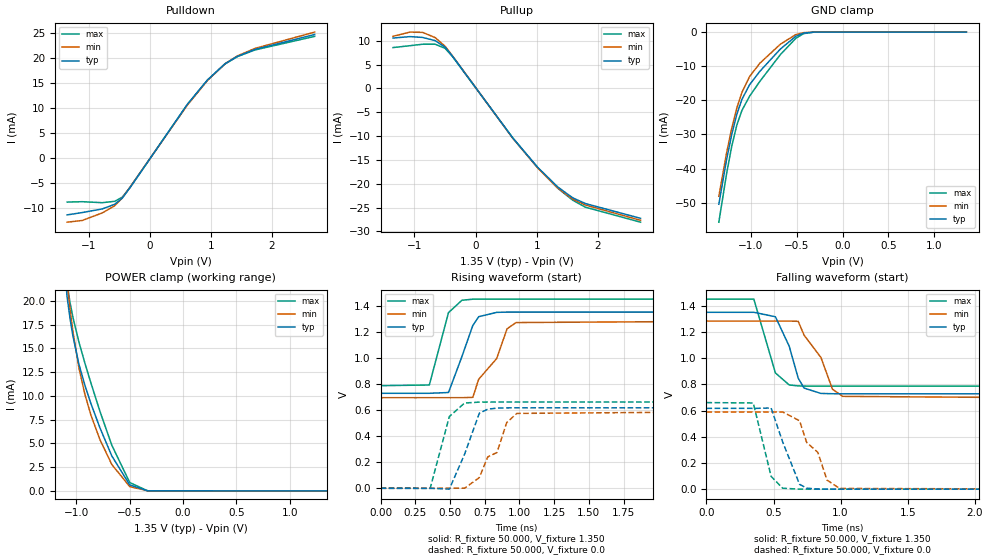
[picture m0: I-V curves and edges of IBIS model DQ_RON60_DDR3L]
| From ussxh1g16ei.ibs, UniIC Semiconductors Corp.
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|   Model DQ_RON60_DDR3L
[Model] DQ_RON60_DDR3L
Model_type I/O
Vinl =  0.540V
Vinh =  0.810V
Vmeas =  0.675V
Rref =  50.000
Vref =  0.675V
C_comp   1.224pF   1.223pF   1.239pF
[Model Spec]
Vinh   0.810V   0.776V   0.860V
Vinl   0.540V   0.506V   0.590V
Vmeas   0.675V   0.641V   0.725V
Vref   0.675V   0.641V   0.725V
Rref   50.000   NA   NA
[Temperature Range]   25.000   95.000   -40.000
[Voltage Range]   1.350V   1.283V   1.450V
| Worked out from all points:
|   slope of the pulldown table from 0 to 0.203 V, typ, clamps not added: 55.3 ohm
|   slope of the pullup table from 0 to 0.203 V, typ, clamps not added: 56.9 ohm
|   GND clamp passes 1 mA (typ) near -0.49 V on its own axis
|   POWER clamp passes 1 mA (typ) near -0.53 V on its own axis
|   rising waveform, R_fixture 50.000, V_fixture 1.350: 20-80 % time 138ps typ, 184ps min, 103ps max; typ from 0.728 V to 1.35 V
|   rising waveform, R_fixture 50.000, V_fixture 0.0: 20-80 % time 132ps typ, 175ps min, 100ps max; typ from 0 V to 0.617 V
|   falling waveform, R_fixture 50.000, V_fixture 1.350: 20-80 % time 140ps typ, 184ps min, 107ps max; typ from 1.35 V to 0.728 V
|   falling waveform, R_fixture 50.000, V_fixture 0.0: 20-80 % time 129ps typ, 173ps min, 96.8ps max; typ from 0.617 V to 0 V
[Pulldown]
|Voltage   I(typ)   I(min)   I(max)
-1.35V    -11.32mA   -12.77mA   -8.765mA
-1.104V   -10.85mA   -12.43mA   -8.687mA
-776mV    -10.13mA   -10.93mA   -8.883mA
-571mV    -9.195mA   -9.485mA   -8.61mA
-448mV    -7.97mA    -7.94mA    -7.779mA
-325mV    -5.951mA   -5.848mA   -5.918mA
618mV     10.72mA    10.58mA    10.69mA
946mV     15.57mA    15.46mA    15.52mA
1.233V    18.79mA    18.79mA    18.74mA
1.438V    20.27mA    20.37mA    20.22mA
1.725V    21.65mA    21.85mA    21.54mA
2.7V      24.61mA    25.09mA    24.24mA
[Pullup]
|Voltage   I(typ)   I(min)   I(max)
-1.35V    10.58mA    10.95mA    8.584mA
-1.072V   10.88mA    11.83mA    8.976mA
-867mV    10.71mA    11.77mA    9.283mA
-662mV    10.05mA    10.69mA    9.288mA
-498mV    8.669mA    8.868mA    8.429mA
-375mV    6.743mA    6.808mA    6.676mA
609mV     -10.37mA   -10.43mA   -10.37mA
1.019V    -16.56mA   -16.69mA   -16.65mA
1.347V    -20.68mA   -20.89mA   -20.95mA
1.593V    -22.96mA   -23.23mA   -23.46mA
1.798V    -24.14mA   -24.45mA   -24.9mA
2.7V      -27.24mA   -27.65mA   -28.05mA
[GND_clamp]
|Voltage   I(typ)   I(min)   I(max)
-1.35V    -50.46mA   -48.12mA   -55.72mA
-1.266V   -37.47mA   -35.5mA    -41.58mA
-1.21V    -30.09mA   -28.26mA   -33.55mA
-1.154V   -24.12mA   -22.27mA   -27.26mA
-1.098V   -19.71mA   -17.66mA   -22.94mA
-1.014V   -15.4mA    -13mA      -18.77mA
-902mV    -11.48mA   -9.107mA   -14.42mA
-678mV    -4.952mA   -3.532mA   -6.573mA
-510mV    -1.223mA   -723.8uA   -1.822mA
-426mV    -288.1uA   -165.1uA   -454.1uA
-314mV    -15.07uA   -12.09uA   -18.31uA
1.35V     0A         0A         0A
[POWER_clamp]
|Voltage   I(typ)   I(min)   I(max)
-1.35V    60.76mA    63.05mA    63.06mA
-1.086V   20.55mA    21.97mA    21.88mA
-1.058V   18.21mA    19.18mA    19.87mA
-1.03V    16.29mA    16.77mA    18.26mA
-974mV    13.34mA    12.95mA    15.67mA
-918mV    11.11mA    10.16mA    13.45mA
-862mV    9.205mA    7.993mA    11.37mA
-778mV    6.661mA    5.422mA    8.404mA
-666mV    3.683mA    2.783mA    4.812mA
-498mV    635.5uA    452.4uA    882.5uA
-330mV    13.33uA    16.29uA    10.16uA
1.35V     0A         0A         0A
[Ramp]
| variable   typ   min   max
dV/dt_r   0.370/0.132n   0.354/0.175n   0.397/0.100n
dV/dt_f   0.373/0.140n   0.353/0.184n   0.398/0.107n
R_load = 50.000
[Rising Waveform]
R_fixture= 50.000
V_fixture= 1.350
V_fixture_min= 1.283
V_fixture_max= 1.450
|time   V(typ)   V(min)   V(max)
0s        727.9mV    694.2mV    786.3mV
351ps     727.9mV    694.2mV    791.5mV
489ps     734mV      694.2mV    1.346V
586ps     1.01V      694.4mV    1.441V
664ps     1.247V     696.8mV    1.449V
707ps     1.315V     836.1mV    1.45V
836ps     1.348V     993.5mV    1.45V
911ps     1.35V      1.222V     1.45V
976ps     1.35V      1.27V      1.45V
3ns       1.35V      1.283V     1.45V
[Rising Waveform]
R_fixture= 50.000
V_fixture= 0.0
V_fixture_min= 0.0
V_fixture_max= 0.0
|time   V(typ)   V(min)   V(max)
0s        129nV      580.1nV    52.27nV
357ps     6.955uV    5.53uV     -989.3uV
495ps     -6.806mV   256.6nV    549.8mV
605ps     261.4mV    687.7uV    653.4mV
711ps     574.8mV    81.59mV    660.3mV
772ps     606.3mV    240.5mV    660.8mV
839ps     614.2mV    274.7mV    660.9mV
908ps     616.1mV    502.8mV    660.9mV
981ps     616.5mV    573.7mV    660.9mV
3ns       616.6mV    589.4mV    660.9mV
[Falling Waveform]
R_fixture= 50.000
V_fixture= 1.350
V_fixture_min= 1.283
V_fixture_max= 1.450
|time   V(typ)   V(min)   V(max)
0s        1.35V      1.283V     1.45V
353ps     1.35V      1.283V     1.451V
514ps     1.316V     1.283V     887.2mV
617ps     1.091V     1.283V     795.4mV
684ps     846.9mV    1.281V     788.2mV
728ps     771.4mV    1.175V     787mV
853ps     730.8mV    1.006V     786.3mV
939ps     728.4mV    763.7mV    786.3mV
1.015ns   728mV      708.3mV    786.3mV
3ns       727.9mV    694.2mV    786.3mV
[Falling Waveform]
R_fixture= 50.000
V_fixture= 0.0
V_fixture_min= 0.0
V_fixture_max= 0.0
|time   V(typ)   V(min)   V(max)
0s        616.6mV    589.4mV    660.9mV
349ps     616.6mV    589.4mV    657.9mV
482ps     619.4mV    589.4mV    97.77mV
568ps     360.8mV    589.2mV    7.242mV
694ps     37.07mV    522.2mV    154.2uV
747ps     7.802mV    356.4mV    29.96uV
830ps     673.3uV    281.3mV    2.584uV
899ps     86uV       69.15mV    543.4nV
992ps     5.694uV    5.445mV    278.8nV
3ns       294.5nV    659.8nV    239.6nV
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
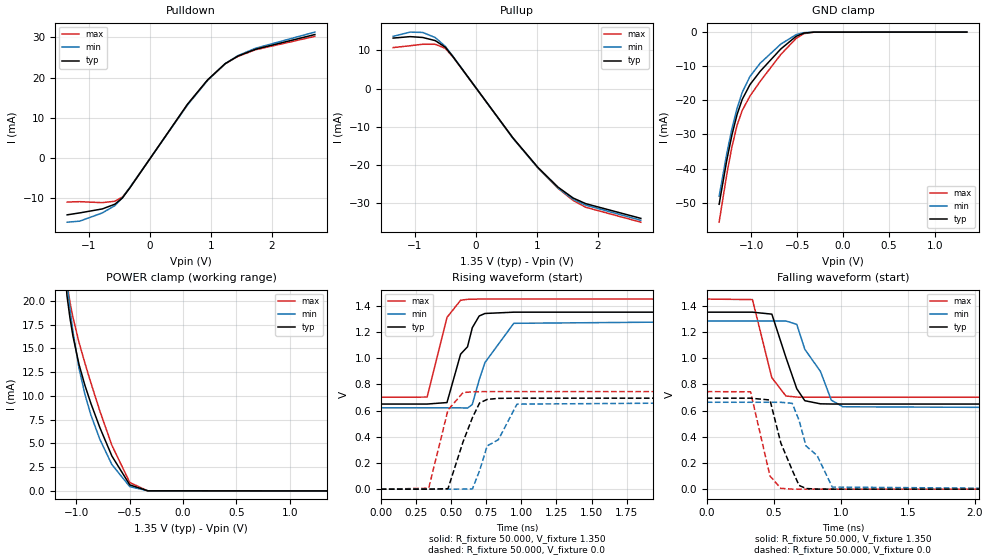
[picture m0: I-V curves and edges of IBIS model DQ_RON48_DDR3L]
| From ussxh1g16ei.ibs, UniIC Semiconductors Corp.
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|   Model DQ_RON48_DDR3L
[Model] DQ_RON48_DDR3L
Model_type I/O
Vinl =  0.540V
Vinh =  0.810V
Vmeas =  0.675V
Rref =  50.000
Vref =  0.675V
C_comp   1.224pF   1.223pF   1.239pF
[Model Spec]
Vinh   0.810V   0.776V   0.860V
Vinl   0.540V   0.506V   0.590V
Vmeas   0.675V   0.641V   0.725V
Vref   0.675V   0.641V   0.725V
Rref   50.000   NA   NA
[Temperature Range]   25.000   95.000   -40.000
[Voltage Range]   1.350V   1.283V   1.450V
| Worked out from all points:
|   slope of the pulldown table from 0 to 0.203 V, typ, clamps not added: 44.3 ohm
|   slope of the pullup table from 0 to 0.203 V, typ, clamps not added: 45.6 ohm
|   GND clamp passes 1 mA (typ) near -0.49 V on its own axis
|   POWER clamp passes 1 mA (typ) near -0.53 V on its own axis
|   rising waveform, R_fixture 50.000, V_fixture 1.350: 20-80 % time 140ps typ, 189ps min, 103ps max; typ from 0.649 V to 1.35 V
|   rising waveform, R_fixture 50.000, V_fixture 0.0: 20-80 % time 136ps typ, 182ps min, 102ps max; typ from 0 V to 0.694 V
|   falling waveform, R_fixture 50.000, V_fixture 1.350: 20-80 % time 141ps typ, 188ps min, 106ps max; typ from 1.35 V to 0.649 V
|   falling waveform, R_fixture 50.000, V_fixture 0.0: 20-80 % time 132ps typ, 178ps min, 96.3ps max; typ from 0.694 V to 0 V
[Pulldown]
|Voltage   I(typ)   I(min)   I(max)
-1.35V    -14.13mA   -15.96mA   -10.95mA
-1.145V   -13.65mA   -15.7mA    -10.85mA
-776mV    -12.66mA   -13.66mA   -11.1mA
-571mV    -11.49mA   -11.85mA   -10.76mA
-448mV    -9.956mA   -9.918mA   -9.718mA
-325mV    -7.433mA   -7.305mA   -7.392mA
618mV     13.39mA    13.21mA    13.35mA
946mV     19.45mA    19.31mA    19.38mA
1.233V    23.48mA    23.48mA    23.42mA
1.438V    25.33mA    25.45mA    25.26mA
1.725V    27.05mA    27.3mA     26.92mA
2.7V      30.73mA    31.34mA    30.27mA
[Pullup]
|Voltage   I(typ)   I(min)   I(max)
-1.35V    13.22mA    13.67mA    10.73mA
-1.072V   13.6mA     14.79mA    11.22mA
-867mV    13.38mA    14.7mA     11.6mA
-662mV    12.56mA    13.36mA    11.6mA
-498mV    10.83mA    11.07mA    10.53mA
-375mV    8.421mA    8.501mA    8.337mA
609mV     -12.94mA   -13.03mA   -12.95mA
1.019V    -20.68mA   -20.84mA   -20.79mA
1.347V    -25.83mA   -26.09mA   -26.16mA
1.593V    -28.67mA   -29mA      -29.3mA
1.798V    -30.14mA   -30.53mA   -31.09mA
2.7V      -34mA      -34.5mA    -35mA
[GND_clamp]
|Voltage   I(typ)   I(min)   I(max)
-1.35V    -50.46mA   -48.12mA   -55.72mA
-1.266V   -37.47mA   -35.5mA    -41.58mA
-1.21V    -30.09mA   -28.26mA   -33.55mA
-1.154V   -24.12mA   -22.27mA   -27.26mA
-1.098V   -19.71mA   -17.66mA   -22.94mA
-1.014V   -15.4mA    -13mA      -18.77mA
-902mV    -11.48mA   -9.107mA   -14.42mA
-678mV    -4.952mA   -3.532mA   -6.573mA
-510mV    -1.223mA   -723.8uA   -1.822mA
-426mV    -288.1uA   -165.1uA   -454.1uA
-314mV    -15.07uA   -12.09uA   -18.31uA
1.35V     0A         0A         0A
[POWER_clamp]
|Voltage   I(typ)   I(min)   I(max)
-1.35V    60.76mA    63.05mA    63.06mA
-1.086V   20.55mA    21.97mA    21.88mA
-1.058V   18.21mA    19.18mA    19.87mA
-1.03V    16.29mA    16.77mA    18.26mA
-974mV    13.34mA    12.95mA    15.67mA
-918mV    11.11mA    10.16mA    13.45mA
-862mV    9.205mA    7.993mA    11.37mA
-778mV    6.661mA    5.422mA    8.404mA
-666mV    3.683mA    2.783mA    4.812mA
-498mV    635.5uA    452.4uA    882.5uA
-330mV    13.33uA    16.29uA    10.16uA
1.35V     0A         0A         0A
[Ramp]
| variable   typ   min   max
dV/dt_r   0.416/0.135n   0.398/0.182n   0.446/0.102n
dV/dt_f   0.420/0.141n   0.398/0.188n   0.449/0.106n
R_load = 50.000
[Rising Waveform]
R_fixture= 50.000
V_fixture= 1.350
V_fixture_min= 1.283
V_fixture_max= 1.450
|time   V(typ)   V(min)   V(max)
0s        649.3mV    620.2mV    701.1mV
330ps     649.3mV    620.2mV    702.3mV
471ps     660.6mV    620.2mV    1.31V
568ps     1.03V      620.4mV    1.441V
617ps     1.086V     618.4mV    1.448V
651ps     1.231V     645.9mV    1.449V
700ps     1.321V     834mV      1.45V
741ps     1.34V      965.7mV    1.45V
946ps     1.35V      1.265V     1.45V
3ns       1.35V      1.283V     1.45V
[Rising Waveform]
R_fixture= 50.000
V_fixture= 0.0
V_fixture_min= 0.0
V_fixture_max= 0.0
|time   V(typ)   V(min)   V(max)
0s        115.5nV    519nV      47.02nV
341ps     13.19uV    7.575uV    7.063mV
478ps     3.474mV    2.062uV    603.8mV
585ps     360mV      608.4uV    736.5mV
652ps     545.7mV    2.233mV    742.8mV
703ps     657.5mV    141.6mV    743.8mV
757ps     684.6mV    329.9mV    744mV
837ps     692.6mV    377.7mV    744.1mV
969ps     694mV      648.8mV    744.1mV
3ns       694mV      662.8mV    744.1mV
[Falling Waveform]
R_fixture= 50.000
V_fixture= 1.350
V_fixture_min= 1.283
V_fixture_max= 1.450
|time   V(typ)   V(min)   V(max)
0s        1.35V      1.283V     1.45V
341ps     1.35V      1.283V     1.446V
486ps     1.335V     1.283V     850.2mV
591ps     1.005V     1.283V     710.7mV
672ps     766.1mV    1.257V     702.3mV
732ps     674.7mV    1.067V     701.4mV
849ps     650.9mV    897.8mV    701.2mV
930ps     649.5mV    678.9mV    701.1mV
1.017ns   649.3mV    628.3mV    701.1mV
3ns       649.3mV    620.2mV    701.1mV
[Falling Waveform]
R_fixture= 50.000
V_fixture= 0.0
V_fixture_min= 0.0
V_fixture_max= 0.0
|time   V(typ)   V(min)   V(max)
0s        694mV      662.8mV    744.1mV
327ps     694mV      662.7mV    742.7mV
472ps     680.1mV    662.8mV    100.4mV
553ps     352mV      662.5mV    6.416mV
638ps     145.5mV    654.9mV    338.9uV
689ps     28.83mV    525.3mV    57.22uV
741ps     5.176mV    329.8mV    9.49uV
824ps     344.7uV    256.3mV    716.5nV
937ps     8.14uV     15.96mV    207.4nV
3ns       236nV      614nV      162.3nV
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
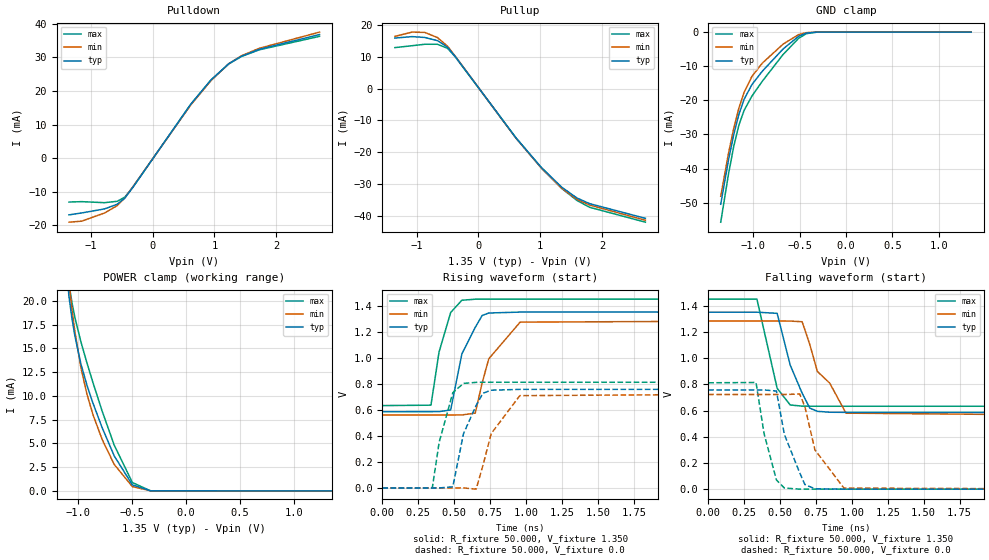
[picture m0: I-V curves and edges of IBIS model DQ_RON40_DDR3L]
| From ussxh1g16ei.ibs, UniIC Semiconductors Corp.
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|   Model DQ_RON40_DDR3L
[Model] DQ_RON40_DDR3L
Model_type I/O
Vinl =  0.540V
Vinh =  0.810V
Vmeas =  0.675V
Rref =  50.000
Vref =  0.675V
C_comp   1.224pF   1.223pF   1.239pF
[Model Spec]
Vinh   0.810V   0.776V   0.860V
Vinl   0.540V   0.506V   0.590V
Vmeas   0.675V   0.641V   0.725V
Vref   0.675V   0.641V   0.725V
Rref   50.000   NA   NA
[Temperature Range]   25.000   95.000   -40.000
[Voltage Range]   1.350V   1.283V   1.450V
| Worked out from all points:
|   slope of the pulldown table from 0 to 0.203 V, typ, clamps not added: 36.9 ohm
|   slope of the pullup table from 0 to 0.203 V, typ, clamps not added: 38 ohm
|   GND clamp passes 1 mA (typ) near -0.49 V on its own axis
|   POWER clamp passes 1 mA (typ) near -0.53 V on its own axis
|   rising waveform, R_fixture 50.000, V_fixture 1.350: 20-80 % time 135ps typ, 186ps min, 97.9ps max; typ from 0.586 V to 1.35 V
|   rising waveform, R_fixture 50.000, V_fixture 0.0: 20-80 % time 130ps typ, 179ps min, 96.1ps max; typ from 0 V to 0.757 V
|   falling waveform, R_fixture 50.000, V_fixture 1.350: 20-80 % time 136ps typ, 183ps min, 99.6ps max; typ from 1.35 V to 0.586 V
|   falling waveform, R_fixture 50.000, V_fixture 0.0: 20-80 % time 127ps typ, 173ps min, 90.8ps max; typ from 0.757 V to 0 V
[Pulldown]
|Voltage   I(typ)   I(min)   I(max)
-1.35V    -16.95mA   -19.14mA   -13.13mA
-1.145V   -16.38mA   -18.83mA   -13.01mA
-776mV    -15.18mA   -16.39mA   -13.32mA
-571mV    -13.78mA   -14.21mA   -12.91mA
-448mV    -11.94mA   -11.89mA   -11.65mA
-325mV    -8.911mA   -8.758mA   -8.862mA
618mV     16.06mA    15.84mA    16.01mA
946mV     23.33mA    23.15mA    23.24mA
1.233V    28.15mA    28.15mA    28.08mA
1.438V    30.37mA    30.51mA    30.3mA
1.725V    32.43mA    32.73mA    32.28mA
2.7V      36.84mA    37.57mA    36.3mA
[Pullup]
|Voltage   I(typ)   I(min)   I(max)
-1.35V    15.86mA    16.4mA     12.87mA
-1.072V   16.32mA    17.74mA    13.46mA
-867mV    16.05mA    17.64mA    13.92mA
-662mV    15.06mA    16.02mA    13.92mA
-498mV    12.98mA    13.28mA    12.63mA
-375mV    10.1mA     10.19mA    9.994mA
609mV     -15.52mA   -15.62mA   -15.52mA
1.019V    -24.79mA   -24.98mA   -24.92mA
1.347V    -30.96mA   -31.27mA   -31.36mA
1.593V    -34.36mA   -34.76mA   -35.13mA
1.798V    -36.13mA   -36.58mA   -37.28mA
2.7V      -40.75mA   -41.34mA   -41.96mA
[GND_clamp]
|Voltage   I(typ)   I(min)   I(max)
-1.35V    -50.46mA   -48.12mA   -55.72mA
-1.266V   -37.47mA   -35.5mA    -41.58mA
-1.21V    -30.09mA   -28.26mA   -33.55mA
-1.154V   -24.12mA   -22.27mA   -27.26mA
-1.098V   -19.71mA   -17.66mA   -22.94mA
-1.014V   -15.4mA    -13mA      -18.77mA
-902mV    -11.48mA   -9.107mA   -14.42mA
-678mV    -4.952mA   -3.532mA   -6.573mA
-510mV    -1.223mA   -723.8uA   -1.822mA
-426mV    -288.1uA   -165.1uA   -454.1uA
-314mV    -15.07uA   -12.09uA   -18.31uA
1.35V     0A         0A         0A
[POWER_clamp]
|Voltage   I(typ)   I(min)   I(max)
-1.35V    60.76mA    63.05mA    63.06mA
-1.086V   20.55mA    21.97mA    21.88mA
-1.058V   18.21mA    19.18mA    19.87mA
-1.03V    16.29mA    16.77mA    18.26mA
-974mV    13.34mA    12.95mA    15.67mA
-918mV    11.11mA    10.16mA    13.45mA
-862mV    9.205mA    7.993mA    11.37mA
-778mV    6.661mA    5.422mA    8.404mA
-666mV    3.683mA    2.783mA    4.812mA
-498mV    635.5uA    452.4uA    882.5uA
-330mV    13.33uA    16.29uA    10.16uA
1.35V     0A         0A         0A
[Ramp]
| variable   typ   min   max
dV/dt_r   0.454/0.131n   0.433/0.178n   0.487/96.070p
dV/dt_f   0.458/0.136n   0.434/0.183n   0.491/99.504p
R_load = 50.000
[Rising Waveform]
R_fixture= 50.000
V_fixture= 1.350
V_fixture_min= 1.283
V_fixture_max= 1.450
|time   V(typ)   V(min)   V(max)
0s        585.8mV    560.4mV    632.4mV
338ps     585.9mV    560.4mV    635.5mV
394ps     586mV      560.4mV    1.043V
475ps     598.6mV    560.4mV    1.347V
553ps     1.029V     560.6mV    1.441V
646ps     1.233V     574.8mV    1.449V
694ps     1.324V     806.7mV    1.45V
740ps     1.343V     991.4mV    1.45V
958ps     1.35V      1.273V     1.45V
3ns       1.35V      1.283V     1.45V
[Rising Waveform]
R_fixture= 50.000
V_fixture= 0.0
V_fixture_min= 0.0
V_fixture_max= 0.0
|time   V(typ)   V(min)   V(max)
0s        104.7nV    469.8nV    42.78nV
347ps     4.56uV     8.353uV    -637.1uV
395ps     85.74uV    13.47uV    351.2mV
490ps     9.118mV    -14.13uV   731.6mV
564ps     416.3mV    558.8uV    802.7mV
652ps     633.3mV    -9.162mV   810.8mV
699ps     726.9mV    172.2mV    811.4mV
757ps     750.5mV    418.1mV    811.5mV
956ps     756.8mV    708.7mV    811.5mV
3ns       756.8mV    722.2mV    811.5mV
[Falling Waveform]
R_fixture= 50.000
V_fixture= 1.350
V_fixture_min= 1.283
V_fixture_max= 1.450
|time   V(typ)   V(min)   V(max)
0s        1.35V      1.283V     1.45V
339ps     1.35V      1.283V     1.45V
480ps     1.341V     1.283V     769.2mV
571ps     946mV      1.282V     642.2mV
654ps     732mV      1.277V     633.3mV
707ps     618.5mV    1.104V     632.6mV
760ps     593.8mV    898.1mV    632.5mV
846ps     586.8mV    808.8mV    632.4mV
959ps     585.9mV    579.9mV    632.4mV
3ns       585.8mV    560.4mV    632.4mV
[Falling Waveform]
R_fixture= 50.000
V_fixture= 0.0
V_fixture_min= 0.0
V_fixture_max= 0.0
|time   V(typ)   V(min)   V(max)
0s        756.8mV    722.2mV    811.5mV
333ps     756.8mV    722.2mV    813.6mV
389ps     756.6mV    722.2mV    423.2mV
475ps     748.4mV    722.2mV    70.11mV
530ps     418.3mV    722mV      8.663mV
637ps     124.6mV    725.8mV    145.5uV
673ps     35.09mV    629.6mV    36.05uV
743ps     2.77mV     299.3mV    2.528uV
945ps     1.878uV    8.14mV     168.1nV
3ns       188.4nV    546.5nV    123.2nV
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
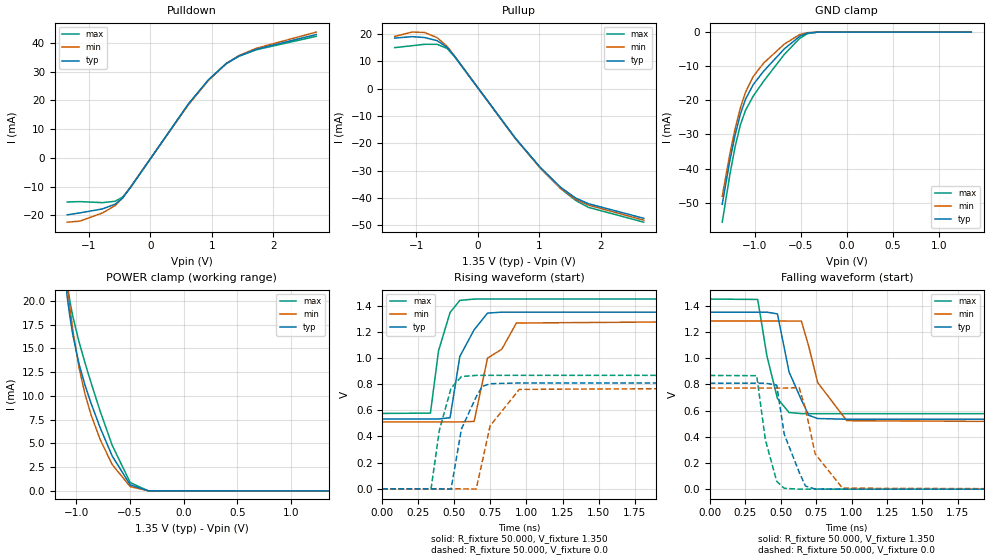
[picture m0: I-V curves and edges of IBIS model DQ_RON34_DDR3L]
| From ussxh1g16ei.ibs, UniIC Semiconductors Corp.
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|   Model DQ_RON34_DDR3L
[Model] DQ_RON34_DDR3L
Model_type I/O
Vinl =  0.540V
Vinh =  0.810V
Vmeas =  0.675V
Rref =  50.000
Vref =  0.675V
C_comp   1.224pF   1.223pF   1.239pF
[Model Spec]
Vinh   0.810V   0.776V   0.860V
Vinl   0.540V   0.506V   0.590V
Vmeas   0.675V   0.641V   0.725V
Vref   0.675V   0.641V   0.725V
Rref   50.000   NA   NA
[Temperature Range]   25.000   95.000   -40.000
[Voltage Range]   1.350V   1.283V   1.450V
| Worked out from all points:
|   slope of the pulldown table from 0 to 0.203 V, typ, clamps not added: 31.7 ohm
|   slope of the pullup table from 0 to 0.203 V, typ, clamps not added: 32.6 ohm
|   GND clamp passes 1 mA (typ) near -0.49 V on its own axis
|   POWER clamp passes 1 mA (typ) near -0.53 V on its own axis
|   rising waveform, R_fixture 50.000, V_fixture 1.350: 20-80 % time 134ps typ, 186ps min, 96.2ps max; typ from 0.534 V to 1.35 V
|   rising waveform, R_fixture 50.000, V_fixture 0.0: 20-80 % time 130ps typ, 179ps min, 94.9ps max; typ from 0 V to 0.809 V
|   falling waveform, R_fixture 50.000, V_fixture 1.350: 20-80 % time 133ps typ, 180ps min, 95.6ps max; typ from 1.35 V to 0.534 V
|   falling waveform, R_fixture 50.000, V_fixture 0.0: 20-80 % time 125ps typ, 171ps min, 88.4ps max; typ from 0.809 V to 0 V
[Pulldown]
|Voltage   I(typ)   I(min)   I(max)
-1.35V    -19.77mA   -22.33mA   -15.31mA
-1.145V   -19.1mA    -21.96mA   -15.17mA
-776mV    -17.71mA   -19.11mA   -15.53mA
-571mV    -16.07mA   -16.57mA   -15.05mA
-448mV    -13.92mA   -13.86mA   -13.59mA
-325mV    -10.39mA   -10.21mA   -10.33mA
618mV     18.72mA    18.46mA    18.66mA
946mV     27.19mA    26.98mA    27.09mA
1.233V    32.82mA    32.81mA    32.73mA
1.438V    35.41mA    35.57mA    35.32mA
1.725V    37.81mA    38.16mA    37.64mA
2.7V      42.94mA    43.78mA    42.31mA
[Pullup]
|Voltage   I(typ)   I(min)   I(max)
-1.35V    18.5mA     19.12mA    15.01mA
-1.072V   19.03mA    20.7mA     15.7mA
-867mV    18.71mA    20.57mA    16.23mA
-662mV    17.56mA    18.68mA    16.23mA
-498mV    15.13mA    15.48mA    14.72mA
-375mV    11.76mA    11.88mA    11.65mA
609mV     -18.08mA   -18.2mA    -18.08mA
1.019V    -28.88mA   -29.11mA   -29.04mA
1.347V    -36.08mA   -36.43mA   -36.54mA
1.593V    -40.04mA   -40.5mA    -40.93mA
1.798V    -42.1mA    -42.62mA   -43.44mA
2.7V      -47.46mA   -48.14mA   -48.88mA
[GND_clamp]
|Voltage   I(typ)   I(min)   I(max)
-1.35V    -50.46mA   -48.12mA   -55.72mA
-1.266V   -37.47mA   -35.5mA    -41.58mA
-1.21V    -30.09mA   -28.26mA   -33.55mA
-1.154V   -24.12mA   -22.27mA   -27.26mA
-1.098V   -19.71mA   -17.66mA   -22.94mA
-1.014V   -15.4mA    -13mA      -18.77mA
-902mV    -11.48mA   -9.107mA   -14.42mA
-678mV    -4.952mA   -3.532mA   -6.573mA
-510mV    -1.223mA   -723.8uA   -1.822mA
-426mV    -288.1uA   -165.1uA   -454.1uA
-314mV    -15.07uA   -12.09uA   -18.31uA
1.35V     0A         0A         0A
[POWER_clamp]
|Voltage   I(typ)   I(min)   I(max)
-1.35V    60.76mA    63.05mA    63.06mA
-1.086V   20.55mA    21.97mA    21.88mA
-1.058V   18.21mA    19.18mA    19.87mA
-1.03V    16.29mA    16.77mA    18.26mA
-974mV    13.34mA    12.95mA    15.67mA
-918mV    11.11mA    10.16mA    13.45mA
-862mV    9.205mA    7.993mA    11.37mA
-778mV    6.661mA    5.422mA    8.404mA
-666mV    3.683mA    2.783mA    4.812mA
-498mV    635.5uA    452.4uA    882.5uA
-330mV    13.33uA    16.29uA    10.16uA
1.35V     0A         0A         0A
[Ramp]
| variable   typ   min   max
dV/dt_r   0.485/0.130n   0.463/0.179n   0.520/94.856p
dV/dt_f   0.490/0.132n   0.463/0.180n   0.524/95.446p
R_load = 50.000
[Rising Waveform]
R_fixture= 50.000
V_fixture= 1.350
V_fixture_min= 1.283
V_fixture_max= 1.450
|time   V(typ)   V(min)   V(max)
0s        533.7mV    511.1mV    576mV
334ps     533.7mV    511.1mV    578.6mV
390ps     533.9mV    511.1mV    1.054V
470ps     543.2mV    511.1mV    1.347V
538ps     1.012V     511.3mV    1.44V
637ps     1.215V     515mV      1.45V
730ps     1.343V     998.9mV    1.45V
829ps     1.35V      1.067V     1.45V
930ps     1.35V      1.267V     1.45V
3ns       1.35V      1.283V     1.45V
[Rising Waveform]
R_fixture= 50.000
V_fixture= 0.0
V_fixture_min= 0.0
V_fixture_max= 0.0
|time   V(typ)   V(min)   V(max)
0s        95.71nV    429.1nV    39.3nV
338ps     22.37uV    10.14uV    -2.215mV
396ps     240.6uV    15.83uV    448.5mV
477ps     -2.659mV   -5.63uV    768.8mV
549ps     457mV      446.4uV    857.9mV
651ps     702mV      -2.325mV   866.8mV
693ps     782mV      205.9mV    867.1mV
748ps     803.2mV    482.3mV    867.1mV
950ps     808.6mV    759.7mV    867.2mV
3ns       808.6mV    771.2mV    867.2mV
[Falling Waveform]
R_fixture= 50.000
V_fixture= 1.350
V_fixture_min= 1.283
V_fixture_max= 1.450
|time   V(typ)   V(min)   V(max)
0s        1.35V      1.283V     1.45V
338ps     1.35V      1.283V     1.447V
403ps     1.35V      1.283V     1.016V
477ps     1.337V     1.283V     692.1mV
559ps     893.9mV    1.282V     584.6mV
646ps     681.2mV    1.282V     576.5mV
698ps     563.3mV    1.089V     576.1mV
761ps     538.6mV    812.8mV    576mV
966ps     533.7mV    522.4mV    576mV
3ns       533.7mV    511.1mV    576mV
[Falling Waveform]
R_fixture= 50.000
V_fixture= 0.0
V_fixture_min= 0.0
V_fixture_max= 0.0
|time   V(typ)   V(min)   V(max)
0s        808.6mV    771.2mV    867.2mV
331ps     808.5mV    771.2mV    865.7mV
392ps     808.2mV    771.2mV    376.3mV
472ps     793.5mV    771.1mV    59.71mV
525ps     418.8mV    770.9mV    6.614mV
630ps     130.8mV    775.1mV    75.03uV
675ps     23.63mV    613.4mV    11.17uV
743ps     1.587mV    269.6mV    762.7nV
936ps     852.3nV    7.514mV    130nV
3ns       -34.23nV   495.5nV    75.89nV
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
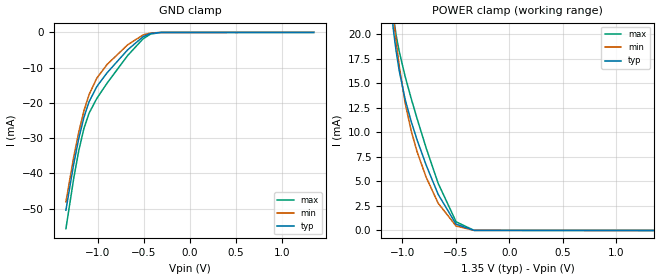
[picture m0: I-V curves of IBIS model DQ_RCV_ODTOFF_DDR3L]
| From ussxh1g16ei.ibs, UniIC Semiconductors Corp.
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|   Model DQ_RCV_ODTOFF_DDR3L
[Model] DQ_RCV_ODTOFF_DDR3L
Model_type Input
Vinl =  0.540V
Vinh =  0.810V
C_comp   1.224pF   1.223pF   1.239pF
[Model Spec]
Vinh   0.810V   0.776V   0.860V
Vinl   0.540V   0.506V   0.590V
[Temperature Range]   25.000   95.000   -40.000
[Voltage Range]   1.350V   1.283V   1.450V
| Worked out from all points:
|   GND clamp passes 1 mA (typ) near -0.49 V on its own axis
|   POWER clamp passes 1 mA (typ) near -0.53 V on its own axis
[GND_clamp]
|Voltage   I(typ)   I(min)   I(max)
-1.35V    -50.46mA   -48.12mA   -55.72mA
-1.266V   -37.47mA   -35.5mA    -41.58mA
-1.21V    -30.09mA   -28.26mA   -33.55mA
-1.154V   -24.12mA   -22.27mA   -27.26mA
-1.098V   -19.71mA   -17.66mA   -22.94mA
-1.014V   -15.4mA    -13mA      -18.77mA
-902mV    -11.48mA   -9.107mA   -14.42mA
-678mV    -4.952mA   -3.532mA   -6.573mA
-510mV    -1.223mA   -723.8uA   -1.822mA
-426mV    -288.1uA   -165.1uA   -454.1uA
-314mV    -15.07uA   -12.09uA   -18.31uA
1.35V     0A         0A         0A
[POWER_clamp]
|Voltage   I(typ)   I(min)   I(max)
-1.35V    60.76mA    63.05mA    63.06mA
-1.086V   20.55mA    21.97mA    21.88mA
-1.058V   18.21mA    19.18mA    19.87mA
-1.03V    16.29mA    16.77mA    18.26mA
-974mV    13.34mA    12.95mA    15.67mA
-918mV    11.11mA    10.16mA    13.45mA
-862mV    9.205mA    7.993mA    11.37mA
-778mV    6.661mA    5.422mA    8.404mA
-666mV    3.683mA    2.783mA    4.812mA
-498mV    635.5uA    452.4uA    882.5uA
-330mV    13.33uA    16.29uA    10.16uA
1.35V     0A         0A         0A
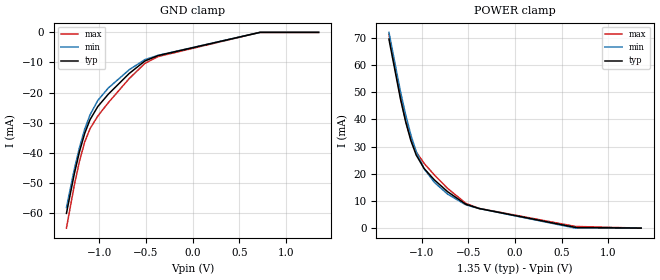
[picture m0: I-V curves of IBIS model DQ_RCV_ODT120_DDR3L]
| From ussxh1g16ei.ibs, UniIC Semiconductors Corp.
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|   Model DQ_RCV_ODT120_DDR3L
[Model] DQ_RCV_ODT120_DDR3L
Model_type Input
Vinl =  0.540V
Vinh =  0.810V
C_comp   1.224pF   1.223pF   1.239pF
[Model Spec]
Vinh   0.810V   0.776V   0.860V
Vinl   0.540V   0.506V   0.590V
[Temperature Range]   25.000   95.000   -40.000
[Voltage Range]   1.350V   1.283V   1.450V
[GND_clamp]
|Voltage   I(typ)   I(min)   I(max)
-1.35V    -60.1mA    -58.18mA   -65mA
-1.266V   -47.01mA   -45.48mA   -50.78mA
-1.21V    -39.55mA   -38.18mA   -42.7mA
-1.154V   -33.5mA    -32.11mA   -36.36mA
-1.098V   -29.02mA   -27.41mA   -32mA
-1.014V   -24.61mA   -22.6mA    -27.77mA
-902mV    -20.53mA   -18.48mA   -23.36mA
-678mV    -13.65mA   -12.41mA   -15.34mA
-510mV    -9.504mA   -9.046mA   -10.31mA
-370mV    -7.712mA   -7.635mA   -8.043mA
722mV     0A         0A         0A
1.35V     0A         0A         0A
[POWER_clamp]
|Voltage   I(typ)   I(min)   I(max)
-1.35V    69.54mA    72.01mA    71.31mA
-1.226V   47.43mA    50.15mA    48.1mA
-1.17V    38.99mA    41.55mA    39.37mA
-1.114V   32.05mA    34.13mA    32.59mA
-1.058V   26.89mA    28.15mA    28.06mA
-974mV    21.95mA    21.87mA    23.84mA
-862mV    17.69mA    16.78mA    19.5mA
-722mV    13.4mA     12.52mA    14.61mA
-526mV    8.771mA    8.554mA    9.101mA
-386mV    7.226mA    7.219mA    7.269mA
650mV     248.1uA    0A         611.8uA
1.35V     0A         0A         0A
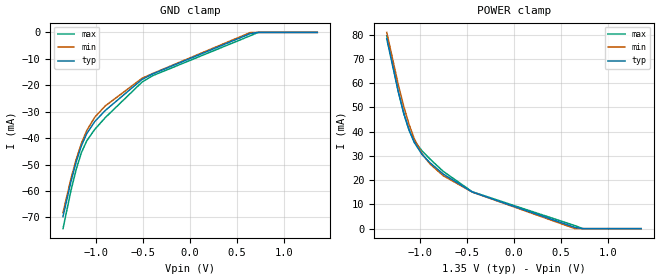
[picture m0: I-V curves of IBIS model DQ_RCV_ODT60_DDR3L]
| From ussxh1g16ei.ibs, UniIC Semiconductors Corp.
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|   Model DQ_RCV_ODT60_DDR3L
[Model] DQ_RCV_ODT60_DDR3L
Model_type Input
Vinl =  0.540V
Vinh =  0.810V
C_comp   1.224pF   1.223pF   1.239pF
[Model Spec]
Vinh   0.810V   0.776V   0.860V
Vinl   0.540V   0.506V   0.590V
[Temperature Range]   25.000   95.000   -40.000
[Voltage Range]   1.350V   1.283V   1.450V
[GND_clamp]
|Voltage   I(typ)   I(min)   I(max)
-1.35V    -69.73mA   -68.22mA   -74.28mA
-1.266V   -56.53mA   -55.44mA   -59.97mA
-1.21V    -49.01mA   -48.08mA   -51.85mA
-1.154V   -42.88mA   -41.94mA   -45.46mA
-1.098V   -38.33mA   -37.15mA   -41.06mA
-1.014V   -33.8mA    -32.18mA   -36.77mA
-902mV    -29.58mA   -27.84mA   -32.29mA
-510mV    -17.77mA   -17.35mA   -18.78mA
-398mV    -15.72mA   -15.57mA   -16.38mA
638mV     -478.2uA   -60.2uA    -1.282mA
722mV     0A         0A         0A
1.35V     0A         0A         0A
[POWER_clamp]
|Voltage   I(typ)   I(min)   I(max)
-1.35V    78.34mA    80.97mA    79.58mA
-1.226V   56.2mA     59.14mA    56.33mA
-1.17V    47.74mA    50.54mA    47.59mA
-1.114V   40.76mA    43.12mA    40.8mA
-1.058V   35.56mA    37.11mA    36.26mA
-974mV    30.56mA    30.78mA    32.02mA
-890mV    27.17mA    26.67mA    28.7mA
-750mV    22.54mA    21.84mA    23.63mA
-442mV    15.11mA    15.09mA    15.22mA
650mV     495.9uA    0A         1.223mA
734mV     0A         0A         0A
1.35V     0A         0A         0A
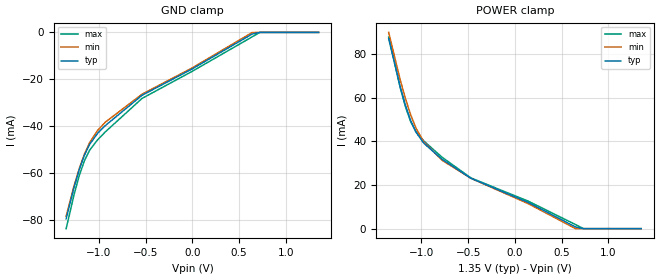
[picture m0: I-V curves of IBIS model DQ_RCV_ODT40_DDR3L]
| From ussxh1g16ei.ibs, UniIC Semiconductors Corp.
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|   Model DQ_RCV_ODT40_DDR3L
[Model] DQ_RCV_ODT40_DDR3L
Model_type Input
Vinl =  0.540V
Vinh =  0.810V
C_comp   1.224pF   1.223pF   1.239pF
[Model Spec]
Vinh   0.810V   0.776V   0.860V
Vinl   0.540V   0.506V   0.590V
[Temperature Range]   25.000   95.000   -40.000
[Voltage Range]   1.350V   1.283V   1.450V
[GND_clamp]
|Voltage   I(typ)   I(min)   I(max)
-1.35V    -79.32mA   -78.22mA   -83.51mA
-1.266V   -66.02mA   -65.37mA   -69.13mA
-1.21V    -58.42mA   -57.95mA   -60.95mA
-1.154V   -52.22mA   -51.73mA   -54.52mA
-1.098V   -47.59mA   -46.85mA   -50.07mA
-1.014V   -42.96mA   -41.72mA   -45.74mA
-930mV    -39.61mA   -38.17mA   -42.29mA
-538mV    -26.75mA   -26.28mA   -28.08mA
-6mV      -15.62mA   -15.2mA    -16.65mA
638mV     -714.4uA   -88.57uA   -1.918mA
722mV     0A         0A         0A
1.35V     0A         0A         0A
[POWER_clamp]
|Voltage   I(typ)   I(min)   I(max)
-1.35V    87.11mA    89.91mA    87.81mA
-1.226V   64.95mA    68.1mA     64.54mA
-1.17V    56.46mA    59.51mA    55.79mA
-1.114V   49.45mA    52.08mA    48.98mA
-1.058V   44.22mA    46.06mA    44.43mA
-974mV    39.14mA    39.68mA    40.17mA
-778mV    31.77mA    31.3mA     32.7mA
-470mV    23.08mA    23.06mA    23.24mA
146mV     11.94mA    11.39mA    12.54mA
650mV     743.3uA    0A         1.832mA
734mV     0A         0A         0A
1.35V     0A         0A         0A
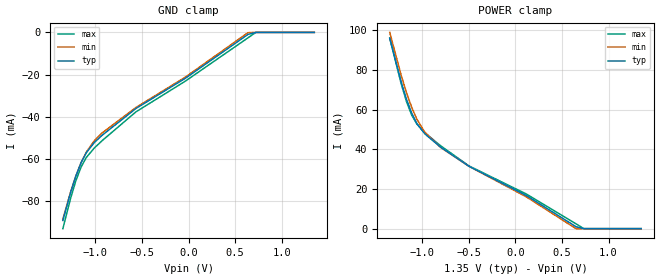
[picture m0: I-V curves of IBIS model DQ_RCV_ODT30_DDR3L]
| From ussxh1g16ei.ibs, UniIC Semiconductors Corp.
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|   Model DQ_RCV_ODT30_DDR3L
[Model] DQ_RCV_ODT30_DDR3L
Model_type Input
Vinl =  0.540V
Vinh =  0.810V
C_comp   1.224pF   1.223pF   1.239pF
[Model Spec]
Vinh   0.810V   0.776V   0.860V
Vinl   0.540V   0.506V   0.590V
[Temperature Range]   25.000   95.000   -40.000
[Voltage Range]   1.350V   1.283V   1.450V
[GND_clamp]
|Voltage   I(typ)   I(min)   I(max)
-1.35V    -89.01mA   -88.32mA   -92.86mA
-1.266V   -75.6mA    -75.39mA   -78.39mA
-1.21V    -67.93mA   -67.91mA   -70.16mA
-1.154V   -61.65mA   -61.61mA   -63.69mA
-1.098V   -56.95mA   -56.64mA   -59.19mA
-1.014V   -52.21mA   -51.35mA   -54.79mA
-930mV    -48.74mA   -47.63mA   -51.29mA
-566mV    -36.03mA   -35.54mA   -37.62mA
-34mV     -21.68mA   -21.14mA   -23.04mA
638mV     -958.1uA   -121.4uA   -2.565mA
722mV     0A         0A         0A
1.35V     0A         0A         0A
[POWER_clamp]
|Voltage   I(typ)   I(min)   I(max)
-1.35V    95.95mA    98.92mA    96.13mA
-1.226V   73.77mA    77.14mA    72.83mA
-1.17V    65.26mA    68.55mA    64.06mA
-1.114V   58.22mA    61.12mA    57.24mA
-1.058V   52.94mA    55.09mA    52.67mA
-974mV    47.8mA     48.65mA    48.39mA
-806mV    41.17mA    41mA       41.87mA
-498mV    31.41mA    31.4mA     31.6mA
118mV     16.68mA    16mA       17.44mA
650mV     989uA      0A         2.443mA
734mV     0A         0A         0A
1.35V     0A         0A         0A
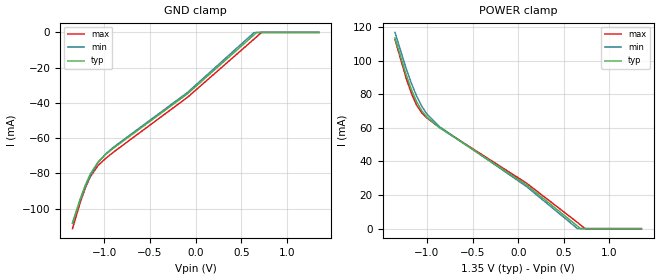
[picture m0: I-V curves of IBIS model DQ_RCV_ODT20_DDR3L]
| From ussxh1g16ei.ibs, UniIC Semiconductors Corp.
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|   Model DQ_RCV_ODT20_DDR3L
[Model] DQ_RCV_ODT20_DDR3L
Model_type Input
Vinl =  0.540V
Vinh =  0.810V
C_comp   1.224pF   1.223pF   1.239pF
[Model Spec]
Vinh   0.810V   0.776V   0.860V
Vinl   0.540V   0.506V   0.590V
[Temperature Range]   25.000   95.000   -40.000
[Voltage Range]   1.350V   1.283V   1.450V
[GND_clamp]
|Voltage   I(typ)   I(min)   I(max)
-1.35V    -108.2mA   -108.3mA   -111.3mA
-1.266V   -94.53mA   -95.2mA    -96.66mA
-1.21V    -86.71mA   -87.59mA   -88.34mA
-1.154V   -80.29mA   -81.14mA   -81.77mA
-1.07V    -73.55mA   -73.86mA   -75.49mA
-986mV    -69.19mA   -68.91mA   -71.45mA
-902mV    -65.67mA   -65.15mA   -67.95mA
-90mV     -34.81mA   -34.06mA   -36.81mA
638mV     -1.428mA   -175.8uA   -3.832mA
666mV     -111.2uA   0A         -2.529mA
722mV     0A         0A         0A
1.35V     0A         0A         0A
[POWER_clamp]
|Voltage   I(typ)   I(min)   I(max)
-1.35V    113.5mA    116.8mA    112.6mA
-1.226V   91.28mA    95.07mA    89.25mA
-1.17V    82.71mA    86.49mA    80.46mA
-1.114V   75.61mA    79.05mA    73.61mA
-1.058V   70.25mA    72.98mA    69.02mA
-1.002V   66.46mA    68.33mA    65.96mA
-862mV    60.12mA    60.69mA    60.21mA
90mV      26.06mA    25.11mA    27.13mA
650mV     1.484mA    0A         3.661mA
678mV     170.7uA    0A         2.375mA
734mV     0A         0A         0A
1.35V     0A         0A         0A
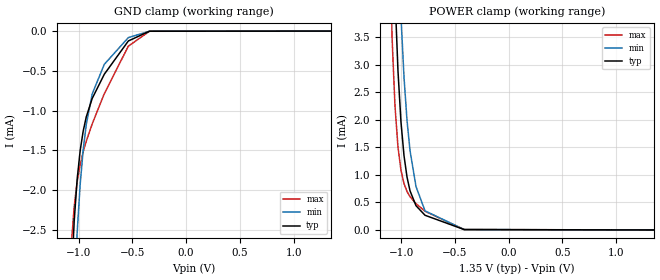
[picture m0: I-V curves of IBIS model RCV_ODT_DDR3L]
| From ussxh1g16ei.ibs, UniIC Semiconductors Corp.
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|   Model RCV_ODT_DDR3L
[Model] RCV_ODT_DDR3L
Model_type Input
Vinl =  0.540V
Vinh =  0.810V
C_comp   0.902pF   0.902pF   0.902pF
[Model Spec]
Vinh   0.810V   0.776V   0.860V
Vinl   0.540V   0.506V   0.590V
[Temperature Range]   25.000   95.000   -40.000
[Voltage Range]   1.350V   1.283V   1.450V
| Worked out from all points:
|   GND clamp passes 1 mA (typ) near -0.91 V on its own axis
|   POWER clamp passes 1 mA (typ) near -0.95 V on its own axis
[GND_clamp]
|Voltage   I(typ)   I(min)   I(max)
-1.35V    -37.62mA   -38.78mA   -37.56mA
-1.07V    -3.19mA    -4.506mA   -2.708mA
-1.042V   -2.392mA   -3.366mA   -2.208mA
-1.014V   -1.858mA   -2.528mA   -1.892mA
-986mV    -1.5mA     -1.923mA   -1.677mA
-958mV    -1.256mA   -1.49mA    -1.517mA
-930mV    -1.081mA   -1.179mA   -1.386mA
-874mV    -846uA     -789uA     -1.166mA
-762mV    -543uA     -418.3uA   -787.7uA
-538mV    -124.2uA   -81.69uA   -189.7uA
-342mV    -1.967uA   -1.796uA   -2.235uA
1.35V     0A         0A         0A
[POWER_clamp]
|Voltage   I(typ)   I(min)   I(max)
-1.35V    52.57mA    56.18mA    49.91mA
-1.086V   6.255mA    9.91mA     3.542mA
-1.058V   4.281mA    7.376mA    2.258mA
-1.03V    2.891mA    5.384mA    1.506mA
-1.002V   1.959mA    3.878mA    1.083mA
-974mV    1.352mA    2.777mA    843.5uA
-946mV    961.9uA    1.993mA    699.7uA
-918mV    711.2uA    1.443mA    604.7uA
-862mV    439.9uA    786.1uA    477.4uA
-778mV    266.7uA    346.5uA    338.9uA
-414mV    7.524uA    6.901uA    8.023uA
1.35V     0A         0A         0A
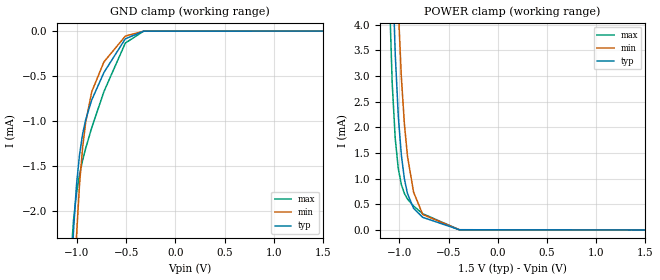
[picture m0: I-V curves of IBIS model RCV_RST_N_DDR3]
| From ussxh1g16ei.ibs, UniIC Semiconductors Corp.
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|   Model RCV_RST_N_DDR3
[Model] RCV_RST_N_DDR3
Model_type Input
Vinl =  0.615V
Vinh =  0.885V
C_comp   0.822pF   0.822pF   0.822pF
[Model Spec]
Vinh   0.885V   0.847V   0.922V
Vinl   0.615V   0.577V   0.652V
[Temperature Range]   25.000   95.000   -40.000
[Voltage Range]   1.500V   1.425V   1.575V
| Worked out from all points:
|   GND clamp passes 1 mA (typ) near -0.91 V on its own axis
|   POWER clamp passes 1 mA (typ) near -0.95 V on its own axis
[GND_clamp]
|Voltage   I(typ)   I(min)   I(max)
-1.5V     -69.37mA   -68.94mA   -71.1mA
-1.066V   -3.056mA   -4.322mA   -2.621mA
-1.035V   -2.238mA   -3.131mA   -2.116mA
-1.004V   -1.714mA   -2.288mA   -1.806mA
-973mV    -1.376mA   -1.704mA   -1.598mA
-942mV    -1.149mA   -1.3mA     -1.44mA
-911mV    -989uA     -1.019mA   -1.307mA
-849mV    -766.8uA   -675.4uA   -1.076mA
-725mV    -460.8uA   -342.9uA   -673.5uA
-508mV    -86.33uA   -55.84uA   -133.3uA
-322mV    -1.052uA   -1.065uA   -1.064uA
1.5V      0A         0A         0A
[POWER_clamp]
|Voltage   I(typ)   I(min)   I(max)
-1.5V     89.87mA    92.1mA     88.82mA
-1.104V   7.876mA    11.84mA    4.749mA
-1.073V   5.259mA    8.664mA    2.865mA
-1.042V   3.423mA    6.175mA    1.777mA
-1.011V   2.217mA    4.314mA    1.194mA
-980mV    1.46mA     2.983mA    884.6uA
-949mV    995.9uA    2.065mA    712.2uA
-918mV    711.2uA    1.443mA    604.7uA
-856mV    421.6uA    739uA      466.1uA
-763mV    246.6uA    302.1uA    317.1uA
-391mV    4.43uA     4.34uA     4.363uA
1.5V      0A         0A         0A
